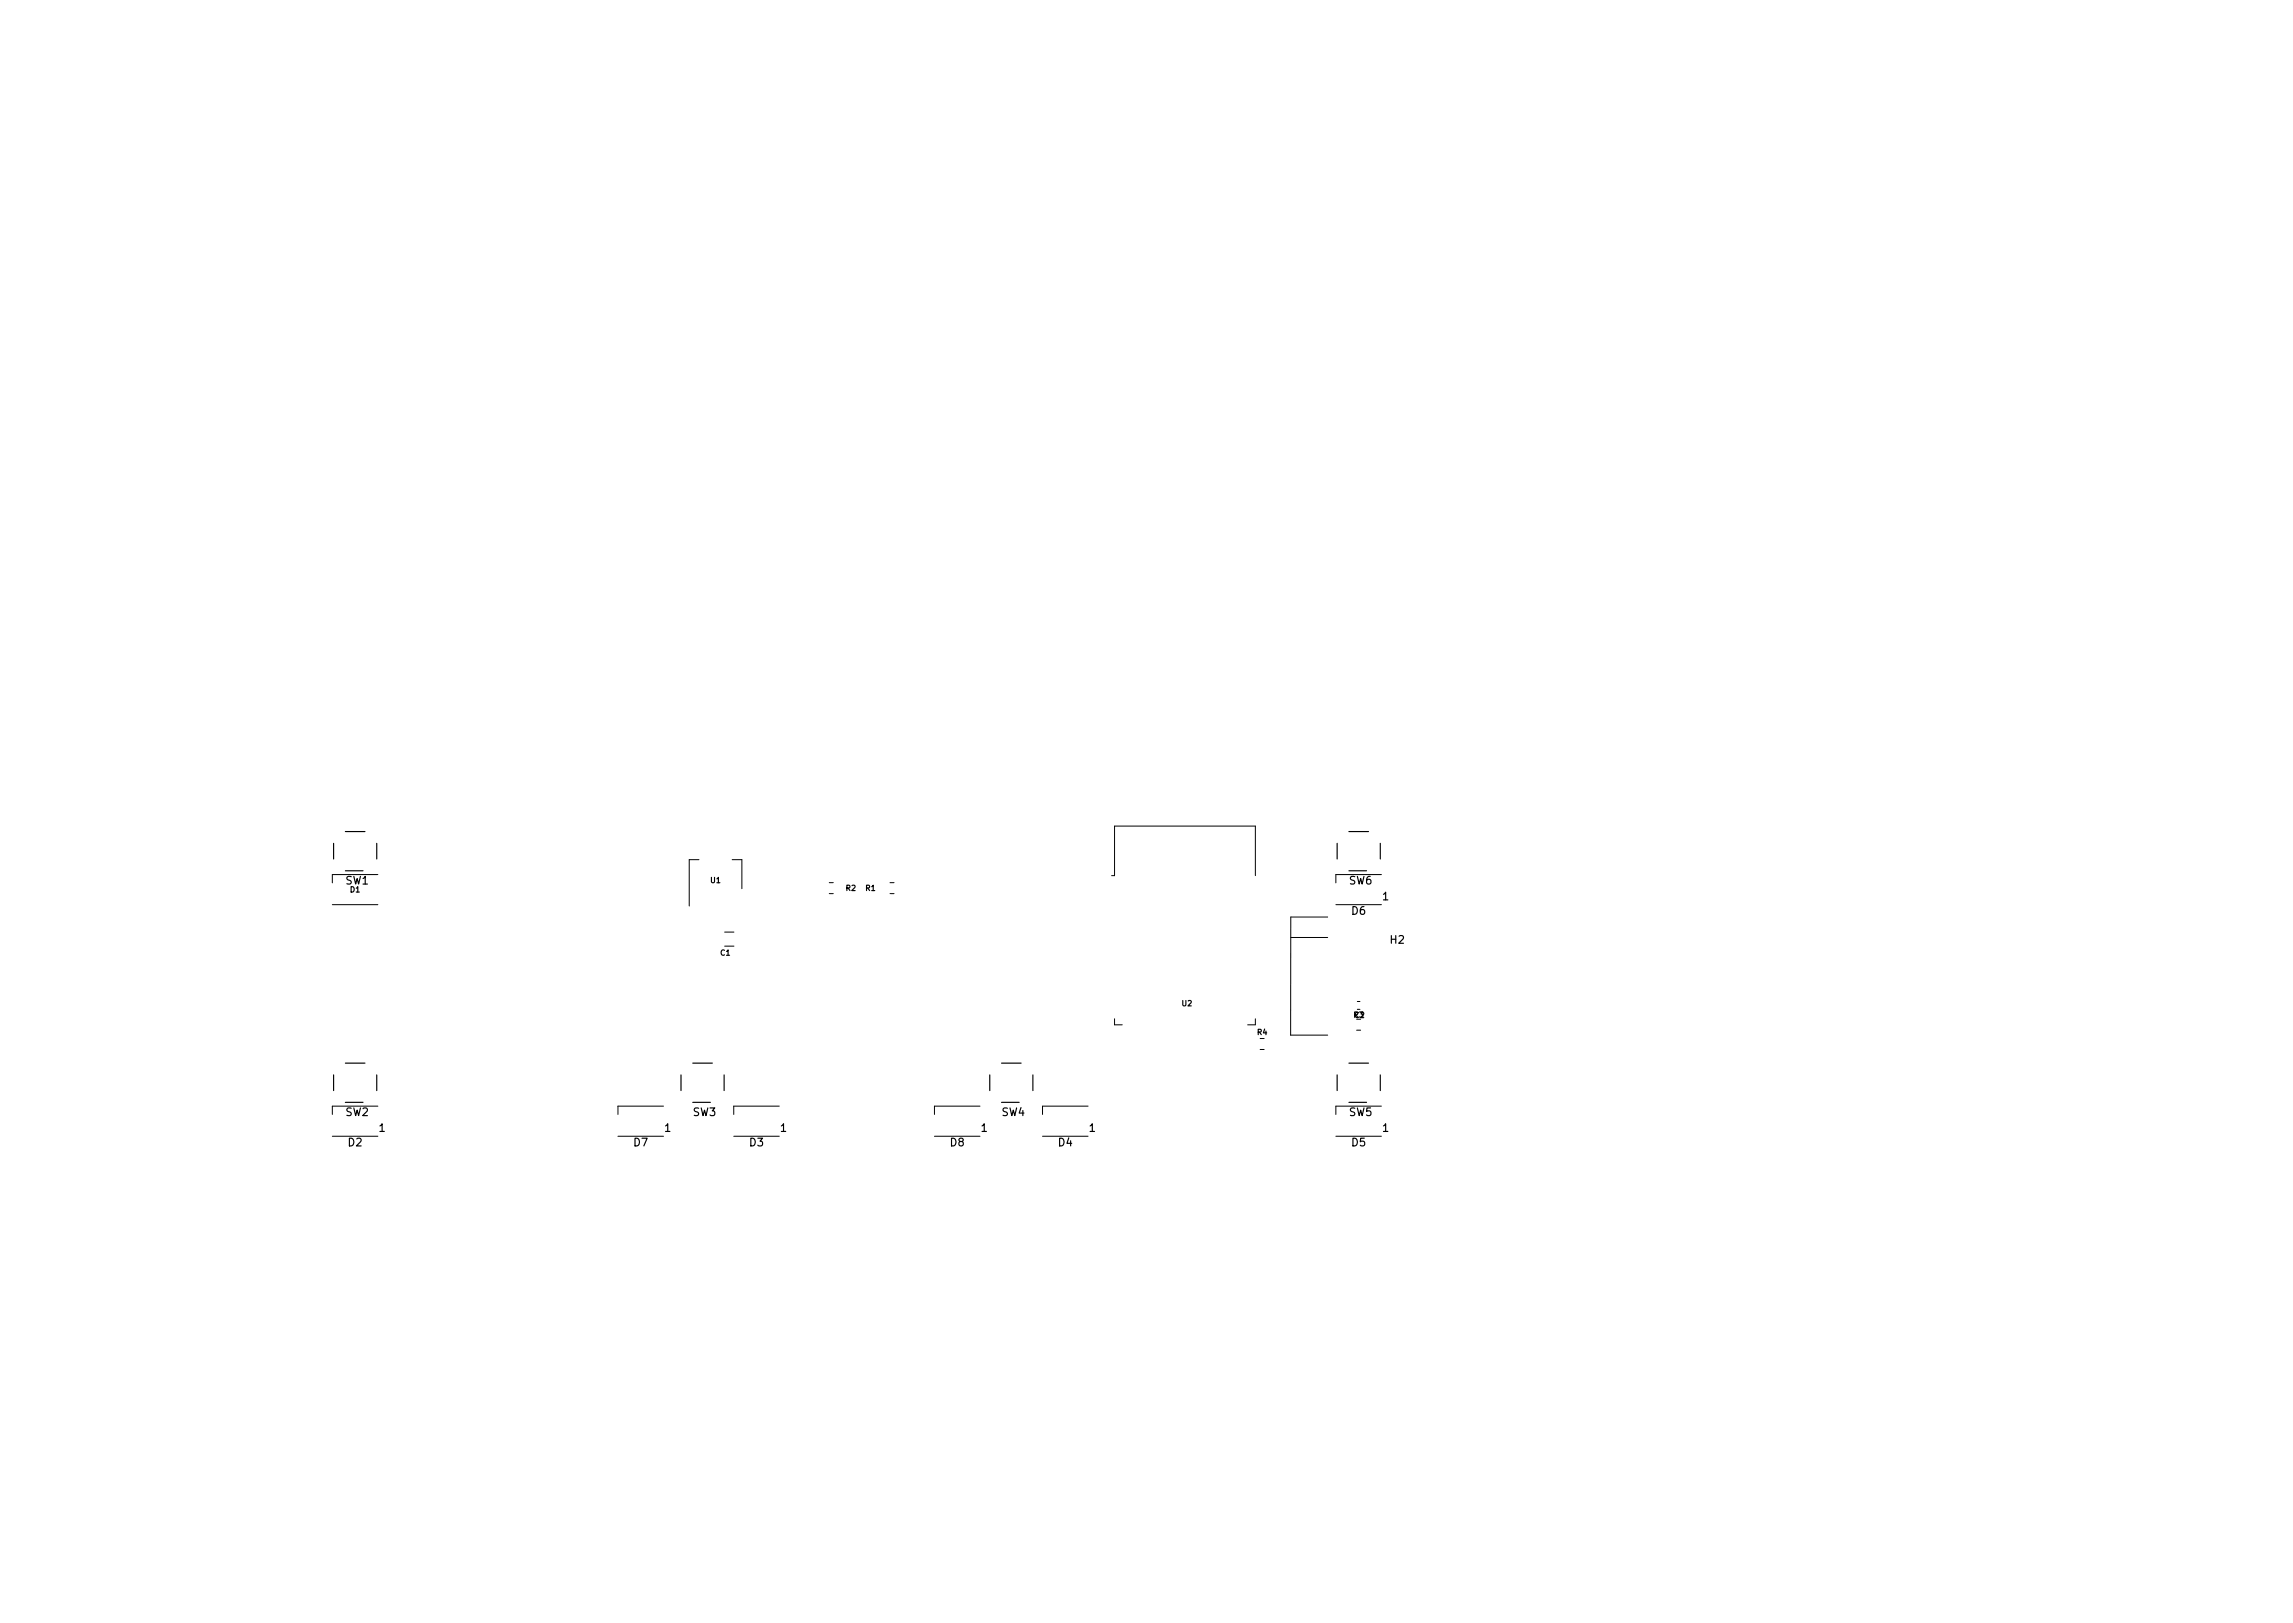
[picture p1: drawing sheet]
<svg xmlns="http://www.w3.org/2000/svg" width="297mm" height="210mm" viewBox="0 0 297 210" stroke-linecap="round" stroke-linejoin="round" font-family="sans-serif">
<defs><g id="words">
<g font-size="1.4">
<text x="44.8" y="114.6">SW1</text>
<text x="174.8" y="114.6">SW6</text>
<text x="175.1" y="118.5">D6</text>
<text x="179.1" y="116.6">1</text>
<text x="180.1" y="122.2">H2</text>
<text x="44.8" y="144.6">SW2</text>
<text x="45.1" y="148.5">D2</text>
<text x="49.1" y="146.6">1</text>
<text x="82.1" y="148.5">D7</text>
<text x="86.1" y="146.6">1</text>
<text x="89.8" y="144.6">SW3</text>
<text x="97.1" y="148.5">D3</text>
<text x="101.1" y="146.6">1</text>
<text x="123.1" y="148.5">D8</text>
<text x="127.1" y="146.6">1</text>
<text x="129.8" y="144.6">SW4</text>
<text x="137.1" y="148.5">D4</text>
<text x="141.1" y="146.6">1</text>
<text x="174.8" y="144.6">SW5</text>
<text x="175.1" y="148.5">D5</text>
<text x="179.1" y="146.6">1</text>
</g>
<g font-size="1">
<text x="45.4" y="115.6">D1</text>
<text x="92.1" y="114.4">U1</text>
<text x="109.6" y="115.4">R2</text>
<text x="112.1" y="115.4">R1</text>
<text x="93.3" y="123.8">C1</text>
<text x="153.1" y="130.3">U2</text>
<text x="175.4" y="131.8">R3</text>
<text x="162.9" y="134.1">R4</text>
</g>
</g></defs>
<g fill="none" stroke="#000" stroke-width=".13">
<path d="M43 117.2h6M49 113.3h-6v1.1M90.5 111.4h-1.2v6M94.8 111.4h1.3v3.7M107.4 114.3h.5M107.4 115.8h.5M115.3 114.3h.5M115.3 115.8h.5M144 113.4h.4v-6.4h18.2v6.4M172 118.8h-4.8v15.3h4.8M173 117.2h6M179 113.3h-6v1.1"/>
<path d="M93.9 120.8h1.2M93.9 122.6h1.2M144.4 132v.8h1M162.6 132v.8h-1M163.2 136h.6M163.2 134.5h.6M167.2 121.4h4.8M175.7 133.5h.6M175.8 129.7h.4M175.8 130.8h.4M43 147.2h6M49 143.3h-6v1.1"/>
<path d="M80 147.2h6M86 143.3h-6v1.1M95.1 147.2h5.9M101 143.3h-5.9v1.1M121.1 147.2h5.8M126.9 143.3h-5.8v1.1M135.1 147.2h5.8M140.9 143.3h-5.8v1.1M173 147.2h6M179 143.3h-6v1.1"/>
</g>
<g fill="none" stroke="#000" stroke-width=".15">
<path d="M43.2 109.3v2M44.7 107.7h2.6M44.7 112.8h2.3M48.8 109.3v2M173.2 109.3v2M174.7 107.7h2.6M174.7 112.8h2.3M178.8 109.3v2M43.2 139.3v2M44.7 137.7h2.6M48.8 139.3v2M88.2 139.3v2"/>
<path d="M89.7 137.7h2.6M93.8 139.3v2M128.2 139.3v2M129.7 137.7h2.6M133.8 139.3v2M173.2 139.3v2M174.7 137.7h2.6M178.8 139.3v2M44.7 142.8h2.3M89.7 142.8h2.3M129.7 142.8h2.3M174.7 142.8h2.3"/>
</g>
<g fill="#fff" stroke="#fff" stroke-width=".13">
<circle cx="119" cy="145.2" r=".17"/>
<circle cx="131" cy="145.2" r=".17"/>
<circle cx="92" cy="145.2" r=".17"/>
<circle cx="71" cy="145.2" r=".17"/>
<circle cx="182.9" cy="109.5" r=".17"/>
<circle cx="54.5" cy="119.9" r=".17"/>
<circle cx="54.5" cy="141.5" r=".17"/>
<circle cx="41.8" cy="114.3" r=".17"/>
<circle cx="135.7" cy="125.5" r=".17"/>
<circle cx="175.6" cy="120.4" r=".17"/>
<circle cx="140.3" cy="118.1" r=".17"/>
<circle cx="173.8" cy="130.2" r=".17"/>
<circle cx="134.2" cy="116.1" r=".17"/>
<circle cx="92.9" cy="119.1" r=".17"/>
<circle cx="181" cy="125.2" r=".18"/>
<circle cx="168.5" cy="132.8" r=".17"/>
<circle cx="168.5" cy="130.3" r=".17"/>
<circle cx="168.5" cy="127.7" r=".17"/>
<circle cx="168.5" cy="125.2" r=".17"/>
<circle cx="168.5" cy="122.7" r=".17"/>
<circle cx="168.5" cy="120.1" r=".17"/>
<circle cx="41" cy="125.2" r=".17"/>
<circle cx="114" cy="110.2" r=".17"/>
</g>
<path d="M106.7 106.5v1.3M106.7 110.4v1M107.9 110.2h.2M115.3 106.5v1.3M115.3 110.5v1" fill="none" stroke="#fff" stroke-width=".6"/>
<use href="#words"/>
</svg>
